# OpenTallas memory compiler (tools/mem_compiler), ASAP7 abstract view
VERSION 5.7 ;
BUSBITCHARS "[]" ;
DIVIDERCHAR "/" ;
PROPERTYDEFINITIONS
  MACRO width INTEGER ;
  MACRO depth INTEGER ;
  MACRO banks INTEGER ;
END PROPERTYDEFINITIONS
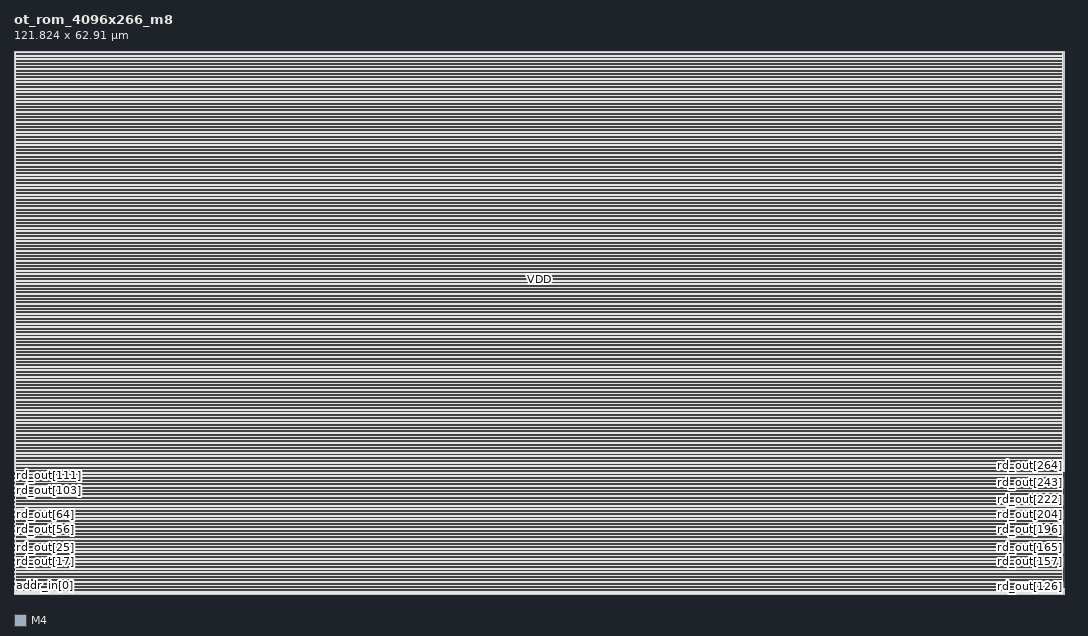
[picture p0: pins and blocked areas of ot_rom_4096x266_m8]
MACRO ot_rom_4096x266_m8
  PROPERTY width 266 ;
  PROPERTY depth 4096 ;
  PROPERTY banks 1 ;
  FOREIGN ot_rom_4096x266_m8 0 0 ;
  SYMMETRY X Y R90 ;
  SIZE 121.824 BY 62.910 ;
  CLASS BLOCK ;
  PIN clk
    DIRECTION INPUT ;
    USE CLOCK ;
    SHAPE ABUTMENT ;
    PORT
      LAYER M4 ;
      RECT 0.000 0.768 0.024 0.792 ;
    END
  END clk
  PIN ce_in
    DIRECTION INPUT ;
    USE SIGNAL ;
    SHAPE ABUTMENT ;
    PORT
      LAYER M4 ;
      RECT 0.000 0.864 0.024 0.888 ;
    END
  END ce_in
  PIN addr_in[0]
    DIRECTION INPUT ;
    USE SIGNAL ;
    SHAPE ABUTMENT ;
    PORT
      LAYER M4 ;
      RECT 0.000 0.960 0.024 0.984 ;
    END
  END addr_in[0]
  PIN addr_in[1]
    DIRECTION INPUT ;
    USE SIGNAL ;
    SHAPE ABUTMENT ;
    PORT
      LAYER M4 ;
      RECT 0.000 1.056 0.024 1.080 ;
    END
  END addr_in[1]
  PIN addr_in[2]
    DIRECTION INPUT ;
    USE SIGNAL ;
    SHAPE ABUTMENT ;
    PORT
      LAYER M4 ;
      RECT 0.000 1.152 0.024 1.176 ;
    END
  END addr_in[2]
  PIN addr_in[3]
    DIRECTION INPUT ;
    USE SIGNAL ;
    SHAPE ABUTMENT ;
    PORT
      LAYER M4 ;
      RECT 0.000 1.248 0.024 1.272 ;
    END
  END addr_in[3]
  PIN addr_in[4]
    DIRECTION INPUT ;
    USE SIGNAL ;
    SHAPE ABUTMENT ;
    PORT
      LAYER M4 ;
      RECT 0.000 1.344 0.024 1.368 ;
    END
  END addr_in[4]
  PIN addr_in[5]
    DIRECTION INPUT ;
    USE SIGNAL ;
    SHAPE ABUTMENT ;
    PORT
      LAYER M4 ;
      RECT 0.000 1.440 0.024 1.464 ;
    END
  END addr_in[5]
  PIN addr_in[6]
    DIRECTION INPUT ;
    USE SIGNAL ;
    SHAPE ABUTMENT ;
    PORT
      LAYER M4 ;
      RECT 0.000 1.536 0.024 1.560 ;
    END
  END addr_in[6]
  PIN addr_in[7]
    DIRECTION INPUT ;
    USE SIGNAL ;
    SHAPE ABUTMENT ;
    PORT
      LAYER M4 ;
      RECT 0.000 1.632 0.024 1.656 ;
    END
  END addr_in[7]
  PIN addr_in[8]
    DIRECTION INPUT ;
    USE SIGNAL ;
    SHAPE ABUTMENT ;
    PORT
      LAYER M4 ;
      RECT 0.000 1.728 0.024 1.752 ;
    END
  END addr_in[8]
  PIN addr_in[9]
    DIRECTION INPUT ;
    USE SIGNAL ;
    SHAPE ABUTMENT ;
    PORT
      LAYER M4 ;
      RECT 0.000 1.824 0.024 1.848 ;
    END
  END addr_in[9]
  PIN addr_in[10]
    DIRECTION INPUT ;
    USE SIGNAL ;
    SHAPE ABUTMENT ;
    PORT
      LAYER M4 ;
      RECT 0.000 1.920 0.024 1.944 ;
    END
  END addr_in[10]
  PIN addr_in[11]
    DIRECTION INPUT ;
    USE SIGNAL ;
    SHAPE ABUTMENT ;
    PORT
      LAYER M4 ;
      RECT 0.000 2.016 0.024 2.040 ;
    END
  END addr_in[11]
  PIN rd_out[0]
    DIRECTION OUTPUT ;
    USE SIGNAL ;
    SHAPE ABUTMENT ;
    PORT
      LAYER M4 ;
      RECT 0.000 2.112 0.024 2.136 ;
    END
  END rd_out[0]
  PIN rd_out[1]
    DIRECTION OUTPUT ;
    USE SIGNAL ;
    SHAPE ABUTMENT ;
    PORT
      LAYER M4 ;
      RECT 0.000 2.208 0.024 2.232 ;
    END
  END rd_out[1]
  PIN rd_out[2]
    DIRECTION OUTPUT ;
    USE SIGNAL ;
    SHAPE ABUTMENT ;
    PORT
      LAYER M4 ;
      RECT 0.000 2.304 0.024 2.328 ;
    END
  END rd_out[2]
  PIN rd_out[3]
    DIRECTION OUTPUT ;
    USE SIGNAL ;
    SHAPE ABUTMENT ;
    PORT
      LAYER M4 ;
      RECT 0.000 2.400 0.024 2.424 ;
    END
  END rd_out[3]
  PIN rd_out[4]
    DIRECTION OUTPUT ;
    USE SIGNAL ;
    SHAPE ABUTMENT ;
    PORT
      LAYER M4 ;
      RECT 0.000 2.496 0.024 2.520 ;
    END
  END rd_out[4]
  PIN rd_out[5]
    DIRECTION OUTPUT ;
    USE SIGNAL ;
    SHAPE ABUTMENT ;
    PORT
      LAYER M4 ;
      RECT 0.000 2.592 0.024 2.616 ;
    END
  END rd_out[5]
  PIN rd_out[6]
    DIRECTION OUTPUT ;
    USE SIGNAL ;
    SHAPE ABUTMENT ;
    PORT
      LAYER M4 ;
      RECT 0.000 2.688 0.024 2.712 ;
    END
  END rd_out[6]
  PIN rd_out[7]
    DIRECTION OUTPUT ;
    USE SIGNAL ;
    SHAPE ABUTMENT ;
    PORT
      LAYER M4 ;
      RECT 0.000 2.784 0.024 2.808 ;
    END
  END rd_out[7]
  PIN rd_out[8]
    DIRECTION OUTPUT ;
    USE SIGNAL ;
    SHAPE ABUTMENT ;
    PORT
      LAYER M4 ;
      RECT 0.000 2.880 0.024 2.904 ;
    END
  END rd_out[8]
  PIN rd_out[9]
    DIRECTION OUTPUT ;
    USE SIGNAL ;
    SHAPE ABUTMENT ;
    PORT
      LAYER M4 ;
      RECT 0.000 2.976 0.024 3.000 ;
    END
  END rd_out[9]
  PIN rd_out[10]
    DIRECTION OUTPUT ;
    USE SIGNAL ;
    SHAPE ABUTMENT ;
    PORT
      LAYER M4 ;
      RECT 0.000 3.072 0.024 3.096 ;
    END
  END rd_out[10]
  PIN rd_out[11]
    DIRECTION OUTPUT ;
    USE SIGNAL ;
    SHAPE ABUTMENT ;
    PORT
      LAYER M4 ;
      RECT 0.000 3.168 0.024 3.192 ;
    END
  END rd_out[11]
  PIN rd_out[12]
    DIRECTION OUTPUT ;
    USE SIGNAL ;
    SHAPE ABUTMENT ;
    PORT
      LAYER M4 ;
      RECT 0.000 3.264 0.024 3.288 ;
    END
  END rd_out[12]
  PIN rd_out[13]
    DIRECTION OUTPUT ;
    USE SIGNAL ;
    SHAPE ABUTMENT ;
    PORT
      LAYER M4 ;
      RECT 0.000 3.360 0.024 3.384 ;
    END
  END rd_out[13]
  PIN rd_out[14]
    DIRECTION OUTPUT ;
    USE SIGNAL ;
    SHAPE ABUTMENT ;
    PORT
      LAYER M4 ;
      RECT 0.000 3.456 0.024 3.480 ;
    END
  END rd_out[14]
  PIN rd_out[15]
    DIRECTION OUTPUT ;
    USE SIGNAL ;
    SHAPE ABUTMENT ;
    PORT
      LAYER M4 ;
      RECT 0.000 3.552 0.024 3.576 ;
    END
  END rd_out[15]
  PIN rd_out[16]
    DIRECTION OUTPUT ;
    USE SIGNAL ;
    SHAPE ABUTMENT ;
    PORT
      LAYER M4 ;
      RECT 0.000 3.648 0.024 3.672 ;
    END
  END rd_out[16]
  PIN rd_out[17]
    DIRECTION OUTPUT ;
    USE SIGNAL ;
    SHAPE ABUTMENT ;
    PORT
      LAYER M4 ;
      RECT 0.000 3.744 0.024 3.768 ;
    END
  END rd_out[17]
  PIN rd_out[18]
    DIRECTION OUTPUT ;
    USE SIGNAL ;
    SHAPE ABUTMENT ;
    PORT
      LAYER M4 ;
      RECT 0.000 3.840 0.024 3.864 ;
    END
  END rd_out[18]
  PIN rd_out[19]
    DIRECTION OUTPUT ;
    USE SIGNAL ;
    SHAPE ABUTMENT ;
    PORT
      LAYER M4 ;
      RECT 0.000 3.936 0.024 3.960 ;
    END
  END rd_out[19]
  PIN rd_out[20]
    DIRECTION OUTPUT ;
    USE SIGNAL ;
    SHAPE ABUTMENT ;
    PORT
      LAYER M4 ;
      RECT 0.000 4.032 0.024 4.056 ;
    END
  END rd_out[20]
  PIN rd_out[21]
    DIRECTION OUTPUT ;
    USE SIGNAL ;
    SHAPE ABUTMENT ;
    PORT
      LAYER M4 ;
      RECT 0.000 4.128 0.024 4.152 ;
    END
  END rd_out[21]
  PIN rd_out[22]
    DIRECTION OUTPUT ;
    USE SIGNAL ;
    SHAPE ABUTMENT ;
    PORT
      LAYER M4 ;
      RECT 0.000 4.224 0.024 4.248 ;
    END
  END rd_out[22]
  PIN rd_out[23]
    DIRECTION OUTPUT ;
    USE SIGNAL ;
    SHAPE ABUTMENT ;
    PORT
      LAYER M4 ;
      RECT 0.000 4.320 0.024 4.344 ;
    END
  END rd_out[23]
  PIN rd_out[24]
    DIRECTION OUTPUT ;
    USE SIGNAL ;
    SHAPE ABUTMENT ;
    PORT
      LAYER M4 ;
      RECT 0.000 4.416 0.024 4.440 ;
    END
  END rd_out[24]
  PIN rd_out[25]
    DIRECTION OUTPUT ;
    USE SIGNAL ;
    SHAPE ABUTMENT ;
    PORT
      LAYER M4 ;
      RECT 0.000 4.512 0.024 4.536 ;
    END
  END rd_out[25]
  PIN rd_out[26]
    DIRECTION OUTPUT ;
    USE SIGNAL ;
    SHAPE ABUTMENT ;
    PORT
      LAYER M4 ;
      RECT 0.000 4.608 0.024 4.632 ;
    END
  END rd_out[26]
  PIN rd_out[27]
    DIRECTION OUTPUT ;
    USE SIGNAL ;
    SHAPE ABUTMENT ;
    PORT
      LAYER M4 ;
      RECT 0.000 4.704 0.024 4.728 ;
    END
  END rd_out[27]
  PIN rd_out[28]
    DIRECTION OUTPUT ;
    USE SIGNAL ;
    SHAPE ABUTMENT ;
    PORT
      LAYER M4 ;
      RECT 0.000 4.800 0.024 4.824 ;
    END
  END rd_out[28]
  PIN rd_out[29]
    DIRECTION OUTPUT ;
    USE SIGNAL ;
    SHAPE ABUTMENT ;
    PORT
      LAYER M4 ;
      RECT 0.000 4.896 0.024 4.920 ;
    END
  END rd_out[29]
  PIN rd_out[30]
    DIRECTION OUTPUT ;
    USE SIGNAL ;
    SHAPE ABUTMENT ;
    PORT
      LAYER M4 ;
      RECT 0.000 4.992 0.024 5.016 ;
    END
  END rd_out[30]
  PIN rd_out[31]
    DIRECTION OUTPUT ;
    USE SIGNAL ;
    SHAPE ABUTMENT ;
    PORT
      LAYER M4 ;
      RECT 0.000 5.088 0.024 5.112 ;
    END
  END rd_out[31]
  PIN rd_out[32]
    DIRECTION OUTPUT ;
    USE SIGNAL ;
    SHAPE ABUTMENT ;
    PORT
      LAYER M4 ;
      RECT 0.000 5.184 0.024 5.208 ;
    END
  END rd_out[32]
  PIN rd_out[33]
    DIRECTION OUTPUT ;
    USE SIGNAL ;
    SHAPE ABUTMENT ;
    PORT
      LAYER M4 ;
      RECT 0.000 5.280 0.024 5.304 ;
    END
  END rd_out[33]
  PIN rd_out[34]
    DIRECTION OUTPUT ;
    USE SIGNAL ;
    SHAPE ABUTMENT ;
    PORT
      LAYER M4 ;
      RECT 0.000 5.376 0.024 5.400 ;
    END
  END rd_out[34]
  PIN rd_out[35]
    DIRECTION OUTPUT ;
    USE SIGNAL ;
    SHAPE ABUTMENT ;
    PORT
      LAYER M4 ;
      RECT 0.000 5.472 0.024 5.496 ;
    END
  END rd_out[35]
  PIN rd_out[36]
    DIRECTION OUTPUT ;
    USE SIGNAL ;
    SHAPE ABUTMENT ;
    PORT
      LAYER M4 ;
      RECT 0.000 5.568 0.024 5.592 ;
    END
  END rd_out[36]
  PIN rd_out[37]
    DIRECTION OUTPUT ;
    USE SIGNAL ;
    SHAPE ABUTMENT ;
    PORT
      LAYER M4 ;
      RECT 0.000 5.664 0.024 5.688 ;
    END
  END rd_out[37]
  PIN rd_out[38]
    DIRECTION OUTPUT ;
    USE SIGNAL ;
    SHAPE ABUTMENT ;
    PORT
      LAYER M4 ;
      RECT 0.000 5.760 0.024 5.784 ;
    END
  END rd_out[38]
  PIN rd_out[39]
    DIRECTION OUTPUT ;
    USE SIGNAL ;
    SHAPE ABUTMENT ;
    PORT
      LAYER M4 ;
      RECT 0.000 5.856 0.024 5.880 ;
    END
  END rd_out[39]
  PIN rd_out[40]
    DIRECTION OUTPUT ;
    USE SIGNAL ;
    SHAPE ABUTMENT ;
    PORT
      LAYER M4 ;
      RECT 0.000 5.952 0.024 5.976 ;
    END
  END rd_out[40]
  PIN rd_out[41]
    DIRECTION OUTPUT ;
    USE SIGNAL ;
    SHAPE ABUTMENT ;
    PORT
      LAYER M4 ;
      RECT 0.000 6.048 0.024 6.072 ;
    END
  END rd_out[41]
  PIN rd_out[42]
    DIRECTION OUTPUT ;
    USE SIGNAL ;
    SHAPE ABUTMENT ;
    PORT
      LAYER M4 ;
      RECT 0.000 6.144 0.024 6.168 ;
    END
  END rd_out[42]
  PIN rd_out[43]
    DIRECTION OUTPUT ;
    USE SIGNAL ;
    SHAPE ABUTMENT ;
    PORT
      LAYER M4 ;
      RECT 0.000 6.240 0.024 6.264 ;
    END
  END rd_out[43]
  PIN rd_out[44]
    DIRECTION OUTPUT ;
    USE SIGNAL ;
    SHAPE ABUTMENT ;
    PORT
      LAYER M4 ;
      RECT 0.000 6.336 0.024 6.360 ;
    END
  END rd_out[44]
  PIN rd_out[45]
    DIRECTION OUTPUT ;
    USE SIGNAL ;
    SHAPE ABUTMENT ;
    PORT
      LAYER M4 ;
      RECT 0.000 6.432 0.024 6.456 ;
    END
  END rd_out[45]
  PIN rd_out[46]
    DIRECTION OUTPUT ;
    USE SIGNAL ;
    SHAPE ABUTMENT ;
    PORT
      LAYER M4 ;
      RECT 0.000 6.528 0.024 6.552 ;
    END
  END rd_out[46]
  PIN rd_out[47]
    DIRECTION OUTPUT ;
    USE SIGNAL ;
    SHAPE ABUTMENT ;
    PORT
      LAYER M4 ;
      RECT 0.000 6.624 0.024 6.648 ;
    END
  END rd_out[47]
  PIN rd_out[48]
    DIRECTION OUTPUT ;
    USE SIGNAL ;
    SHAPE ABUTMENT ;
    PORT
      LAYER M4 ;
      RECT 0.000 6.720 0.024 6.744 ;
    END
  END rd_out[48]
  PIN rd_out[49]
    DIRECTION OUTPUT ;
    USE SIGNAL ;
    SHAPE ABUTMENT ;
    PORT
      LAYER M4 ;
      RECT 0.000 6.816 0.024 6.840 ;
    END
  END rd_out[49]
  PIN rd_out[50]
    DIRECTION OUTPUT ;
    USE SIGNAL ;
    SHAPE ABUTMENT ;
    PORT
      LAYER M4 ;
      RECT 0.000 6.912 0.024 6.936 ;
    END
  END rd_out[50]
  PIN rd_out[51]
    DIRECTION OUTPUT ;
    USE SIGNAL ;
    SHAPE ABUTMENT ;
    PORT
      LAYER M4 ;
      RECT 0.000 7.008 0.024 7.032 ;
    END
  END rd_out[51]
  PIN rd_out[52]
    DIRECTION OUTPUT ;
    USE SIGNAL ;
    SHAPE ABUTMENT ;
    PORT
      LAYER M4 ;
      RECT 0.000 7.104 0.024 7.128 ;
    END
  END rd_out[52]
  PIN rd_out[53]
    DIRECTION OUTPUT ;
    USE SIGNAL ;
    SHAPE ABUTMENT ;
    PORT
      LAYER M4 ;
      RECT 0.000 7.200 0.024 7.224 ;
    END
  END rd_out[53]
  PIN rd_out[54]
    DIRECTION OUTPUT ;
    USE SIGNAL ;
    SHAPE ABUTMENT ;
    PORT
      LAYER M4 ;
      RECT 0.000 7.296 0.024 7.320 ;
    END
  END rd_out[54]
  PIN rd_out[55]
    DIRECTION OUTPUT ;
    USE SIGNAL ;
    SHAPE ABUTMENT ;
    PORT
      LAYER M4 ;
      RECT 0.000 7.392 0.024 7.416 ;
    END
  END rd_out[55]
  PIN rd_out[56]
    DIRECTION OUTPUT ;
    USE SIGNAL ;
    SHAPE ABUTMENT ;
    PORT
      LAYER M4 ;
      RECT 0.000 7.488 0.024 7.512 ;
    END
  END rd_out[56]
  PIN rd_out[57]
    DIRECTION OUTPUT ;
    USE SIGNAL ;
    SHAPE ABUTMENT ;
    PORT
      LAYER M4 ;
      RECT 0.000 7.584 0.024 7.608 ;
    END
  END rd_out[57]
  PIN rd_out[58]
    DIRECTION OUTPUT ;
    USE SIGNAL ;
    SHAPE ABUTMENT ;
    PORT
      LAYER M4 ;
      RECT 0.000 7.680 0.024 7.704 ;
    END
  END rd_out[58]
  PIN rd_out[59]
    DIRECTION OUTPUT ;
    USE SIGNAL ;
    SHAPE ABUTMENT ;
    PORT
      LAYER M4 ;
      RECT 0.000 7.776 0.024 7.800 ;
    END
  END rd_out[59]
  PIN rd_out[60]
    DIRECTION OUTPUT ;
    USE SIGNAL ;
    SHAPE ABUTMENT ;
    PORT
      LAYER M4 ;
      RECT 0.000 7.872 0.024 7.896 ;
    END
  END rd_out[60]
  PIN rd_out[61]
    DIRECTION OUTPUT ;
    USE SIGNAL ;
    SHAPE ABUTMENT ;
    PORT
      LAYER M4 ;
      RECT 0.000 7.968 0.024 7.992 ;
    END
  END rd_out[61]
  PIN rd_out[62]
    DIRECTION OUTPUT ;
    USE SIGNAL ;
    SHAPE ABUTMENT ;
    PORT
      LAYER M4 ;
      RECT 0.000 8.064 0.024 8.088 ;
    END
  END rd_out[62]
  PIN rd_out[63]
    DIRECTION OUTPUT ;
    USE SIGNAL ;
    SHAPE ABUTMENT ;
    PORT
      LAYER M4 ;
      RECT 0.000 8.160 0.024 8.184 ;
    END
  END rd_out[63]
  PIN rd_out[64]
    DIRECTION OUTPUT ;
    USE SIGNAL ;
    SHAPE ABUTMENT ;
    PORT
      LAYER M4 ;
      RECT 0.000 8.256 0.024 8.280 ;
    END
  END rd_out[64]
  PIN rd_out[65]
    DIRECTION OUTPUT ;
    USE SIGNAL ;
    SHAPE ABUTMENT ;
    PORT
      LAYER M4 ;
      RECT 0.000 8.352 0.024 8.376 ;
    END
  END rd_out[65]
  PIN rd_out[66]
    DIRECTION OUTPUT ;
    USE SIGNAL ;
    SHAPE ABUTMENT ;
    PORT
      LAYER M4 ;
      RECT 0.000 8.448 0.024 8.472 ;
    END
  END rd_out[66]
  PIN rd_out[67]
    DIRECTION OUTPUT ;
    USE SIGNAL ;
    SHAPE ABUTMENT ;
    PORT
      LAYER M4 ;
      RECT 0.000 8.544 0.024 8.568 ;
    END
  END rd_out[67]
  PIN rd_out[68]
    DIRECTION OUTPUT ;
    USE SIGNAL ;
    SHAPE ABUTMENT ;
    PORT
      LAYER M4 ;
      RECT 0.000 8.640 0.024 8.664 ;
    END
  END rd_out[68]
  PIN rd_out[69]
    DIRECTION OUTPUT ;
    USE SIGNAL ;
    SHAPE ABUTMENT ;
    PORT
      LAYER M4 ;
      RECT 0.000 8.736 0.024 8.760 ;
    END
  END rd_out[69]
  PIN rd_out[70]
    DIRECTION OUTPUT ;
    USE SIGNAL ;
    SHAPE ABUTMENT ;
    PORT
      LAYER M4 ;
      RECT 0.000 8.832 0.024 8.856 ;
    END
  END rd_out[70]
  PIN rd_out[71]
    DIRECTION OUTPUT ;
    USE SIGNAL ;
    SHAPE ABUTMENT ;
    PORT
      LAYER M4 ;
      RECT 0.000 8.928 0.024 8.952 ;
    END
  END rd_out[71]
  PIN rd_out[72]
    DIRECTION OUTPUT ;
    USE SIGNAL ;
    SHAPE ABUTMENT ;
    PORT
      LAYER M4 ;
      RECT 0.000 9.024 0.024 9.048 ;
    END
  END rd_out[72]
  PIN rd_out[73]
    DIRECTION OUTPUT ;
    USE SIGNAL ;
    SHAPE ABUTMENT ;
    PORT
      LAYER M4 ;
      RECT 0.000 9.120 0.024 9.144 ;
    END
  END rd_out[73]
  PIN rd_out[74]
    DIRECTION OUTPUT ;
    USE SIGNAL ;
    SHAPE ABUTMENT ;
    PORT
      LAYER M4 ;
      RECT 0.000 9.216 0.024 9.240 ;
    END
  END rd_out[74]
  PIN rd_out[75]
    DIRECTION OUTPUT ;
    USE SIGNAL ;
    SHAPE ABUTMENT ;
    PORT
      LAYER M4 ;
      RECT 0.000 9.312 0.024 9.336 ;
    END
  END rd_out[75]
  PIN rd_out[76]
    DIRECTION OUTPUT ;
    USE SIGNAL ;
    SHAPE ABUTMENT ;
    PORT
      LAYER M4 ;
      RECT 0.000 9.408 0.024 9.432 ;
    END
  END rd_out[76]
  PIN rd_out[77]
    DIRECTION OUTPUT ;
    USE SIGNAL ;
    SHAPE ABUTMENT ;
    PORT
      LAYER M4 ;
      RECT 0.000 9.504 0.024 9.528 ;
    END
  END rd_out[77]
  PIN rd_out[78]
    DIRECTION OUTPUT ;
    USE SIGNAL ;
    SHAPE ABUTMENT ;
    PORT
      LAYER M4 ;
      RECT 0.000 9.600 0.024 9.624 ;
    END
  END rd_out[78]
  PIN rd_out[79]
    DIRECTION OUTPUT ;
    USE SIGNAL ;
    SHAPE ABUTMENT ;
    PORT
      LAYER M4 ;
      RECT 0.000 9.696 0.024 9.720 ;
    END
  END rd_out[79]
  PIN rd_out[80]
    DIRECTION OUTPUT ;
    USE SIGNAL ;
    SHAPE ABUTMENT ;
    PORT
      LAYER M4 ;
      RECT 0.000 9.792 0.024 9.816 ;
    END
  END rd_out[80]
  PIN rd_out[81]
    DIRECTION OUTPUT ;
    USE SIGNAL ;
    SHAPE ABUTMENT ;
    PORT
      LAYER M4 ;
      RECT 0.000 9.888 0.024 9.912 ;
    END
  END rd_out[81]
  PIN rd_out[82]
    DIRECTION OUTPUT ;
    USE SIGNAL ;
    SHAPE ABUTMENT ;
    PORT
      LAYER M4 ;
      RECT 0.000 9.984 0.024 10.008 ;
    END
  END rd_out[82]
  PIN rd_out[83]
    DIRECTION OUTPUT ;
    USE SIGNAL ;
    SHAPE ABUTMENT ;
    PORT
      LAYER M4 ;
      RECT 0.000 10.080 0.024 10.104 ;
    END
  END rd_out[83]
  PIN rd_out[84]
    DIRECTION OUTPUT ;
    USE SIGNAL ;
    SHAPE ABUTMENT ;
    PORT
      LAYER M4 ;
      RECT 0.000 10.176 0.024 10.200 ;
    END
  END rd_out[84]
  PIN rd_out[85]
    DIRECTION OUTPUT ;
    USE SIGNAL ;
    SHAPE ABUTMENT ;
    PORT
      LAYER M4 ;
      RECT 0.000 10.272 0.024 10.296 ;
    END
  END rd_out[85]
  PIN rd_out[86]
    DIRECTION OUTPUT ;
    USE SIGNAL ;
    SHAPE ABUTMENT ;
    PORT
      LAYER M4 ;
      RECT 0.000 10.368 0.024 10.392 ;
    END
  END rd_out[86]
  PIN rd_out[87]
    DIRECTION OUTPUT ;
    USE SIGNAL ;
    SHAPE ABUTMENT ;
    PORT
      LAYER M4 ;
      RECT 0.000 10.464 0.024 10.488 ;
    END
  END rd_out[87]
  PIN rd_out[88]
    DIRECTION OUTPUT ;
    USE SIGNAL ;
    SHAPE ABUTMENT ;
    PORT
      LAYER M4 ;
      RECT 0.000 10.560 0.024 10.584 ;
    END
  END rd_out[88]
  PIN rd_out[89]
    DIRECTION OUTPUT ;
    USE SIGNAL ;
    SHAPE ABUTMENT ;
    PORT
      LAYER M4 ;
      RECT 0.000 10.656 0.024 10.680 ;
    END
  END rd_out[89]
  PIN rd_out[90]
    DIRECTION OUTPUT ;
    USE SIGNAL ;
    SHAPE ABUTMENT ;
    PORT
      LAYER M4 ;
      RECT 0.000 10.752 0.024 10.776 ;
    END
  END rd_out[90]
  PIN rd_out[91]
    DIRECTION OUTPUT ;
    USE SIGNAL ;
    SHAPE ABUTMENT ;
    PORT
      LAYER M4 ;
      RECT 0.000 10.848 0.024 10.872 ;
    END
  END rd_out[91]
  PIN rd_out[92]
    DIRECTION OUTPUT ;
    USE SIGNAL ;
    SHAPE ABUTMENT ;
    PORT
      LAYER M4 ;
      RECT 0.000 10.944 0.024 10.968 ;
    END
  END rd_out[92]
  PIN rd_out[93]
    DIRECTION OUTPUT ;
    USE SIGNAL ;
    SHAPE ABUTMENT ;
    PORT
      LAYER M4 ;
      RECT 0.000 11.040 0.024 11.064 ;
    END
  END rd_out[93]
  PIN rd_out[94]
    DIRECTION OUTPUT ;
    USE SIGNAL ;
    SHAPE ABUTMENT ;
    PORT
      LAYER M4 ;
      RECT 0.000 11.136 0.024 11.160 ;
    END
  END rd_out[94]
  PIN rd_out[95]
    DIRECTION OUTPUT ;
    USE SIGNAL ;
    SHAPE ABUTMENT ;
    PORT
      LAYER M4 ;
      RECT 0.000 11.232 0.024 11.256 ;
    END
  END rd_out[95]
  PIN rd_out[96]
    DIRECTION OUTPUT ;
    USE SIGNAL ;
    SHAPE ABUTMENT ;
    PORT
      LAYER M4 ;
      RECT 0.000 11.328 0.024 11.352 ;
    END
  END rd_out[96]
  PIN rd_out[97]
    DIRECTION OUTPUT ;
    USE SIGNAL ;
    SHAPE ABUTMENT ;
    PORT
      LAYER M4 ;
      RECT 0.000 11.424 0.024 11.448 ;
    END
  END rd_out[97]
  PIN rd_out[98]
    DIRECTION OUTPUT ;
    USE SIGNAL ;
    SHAPE ABUTMENT ;
    PORT
      LAYER M4 ;
      RECT 0.000 11.520 0.024 11.544 ;
    END
  END rd_out[98]
  PIN rd_out[99]
    DIRECTION OUTPUT ;
    USE SIGNAL ;
    SHAPE ABUTMENT ;
    PORT
      LAYER M4 ;
      RECT 0.000 11.616 0.024 11.640 ;
    END
  END rd_out[99]
  PIN rd_out[100]
    DIRECTION OUTPUT ;
    USE SIGNAL ;
    SHAPE ABUTMENT ;
    PORT
      LAYER M4 ;
      RECT 0.000 11.712 0.024 11.736 ;
    END
  END rd_out[100]
  PIN rd_out[101]
    DIRECTION OUTPUT ;
    USE SIGNAL ;
    SHAPE ABUTMENT ;
    PORT
      LAYER M4 ;
      RECT 0.000 11.808 0.024 11.832 ;
    END
  END rd_out[101]
  PIN rd_out[102]
    DIRECTION OUTPUT ;
    USE SIGNAL ;
    SHAPE ABUTMENT ;
    PORT
      LAYER M4 ;
      RECT 0.000 11.904 0.024 11.928 ;
    END
  END rd_out[102]
  PIN rd_out[103]
    DIRECTION OUTPUT ;
    USE SIGNAL ;
    SHAPE ABUTMENT ;
    PORT
      LAYER M4 ;
      RECT 0.000 12.000 0.024 12.024 ;
    END
  END rd_out[103]
  PIN rd_out[104]
    DIRECTION OUTPUT ;
    USE SIGNAL ;
    SHAPE ABUTMENT ;
    PORT
      LAYER M4 ;
      RECT 0.000 12.096 0.024 12.120 ;
    END
  END rd_out[104]
  PIN rd_out[105]
    DIRECTION OUTPUT ;
    USE SIGNAL ;
    SHAPE ABUTMENT ;
    PORT
      LAYER M4 ;
      RECT 0.000 12.192 0.024 12.216 ;
    END
  END rd_out[105]
  PIN rd_out[106]
    DIRECTION OUTPUT ;
    USE SIGNAL ;
    SHAPE ABUTMENT ;
    PORT
      LAYER M4 ;
      RECT 0.000 12.288 0.024 12.312 ;
    END
  END rd_out[106]
  PIN rd_out[107]
    DIRECTION OUTPUT ;
    USE SIGNAL ;
    SHAPE ABUTMENT ;
    PORT
      LAYER M4 ;
      RECT 0.000 12.384 0.024 12.408 ;
    END
  END rd_out[107]
  PIN rd_out[108]
    DIRECTION OUTPUT ;
    USE SIGNAL ;
    SHAPE ABUTMENT ;
    PORT
      LAYER M4 ;
      RECT 0.000 12.480 0.024 12.504 ;
    END
  END rd_out[108]
  PIN rd_out[109]
    DIRECTION OUTPUT ;
    USE SIGNAL ;
    SHAPE ABUTMENT ;
    PORT
      LAYER M4 ;
      RECT 0.000 12.576 0.024 12.600 ;
    END
  END rd_out[109]
  PIN rd_out[110]
    DIRECTION OUTPUT ;
    USE SIGNAL ;
    SHAPE ABUTMENT ;
    PORT
      LAYER M4 ;
      RECT 0.000 12.672 0.024 12.696 ;
    END
  END rd_out[110]
  PIN rd_out[111]
    DIRECTION OUTPUT ;
    USE SIGNAL ;
    SHAPE ABUTMENT ;
    PORT
      LAYER M4 ;
      RECT 0.000 12.768 0.024 12.792 ;
    END
  END rd_out[111]
  PIN rd_out[112]
    DIRECTION OUTPUT ;
    USE SIGNAL ;
    SHAPE ABUTMENT ;
    PORT
      LAYER M4 ;
      RECT 0.000 12.864 0.024 12.888 ;
    END
  END rd_out[112]
  PIN rd_out[113]
    DIRECTION OUTPUT ;
    USE SIGNAL ;
    SHAPE ABUTMENT ;
    PORT
      LAYER M4 ;
      RECT 0.000 12.960 0.024 12.984 ;
    END
  END rd_out[113]
  PIN rd_out[114]
    DIRECTION OUTPUT ;
    USE SIGNAL ;
    SHAPE ABUTMENT ;
    PORT
      LAYER M4 ;
      RECT 0.000 13.056 0.024 13.080 ;
    END
  END rd_out[114]
  PIN rd_out[115]
    DIRECTION OUTPUT ;
    USE SIGNAL ;
    SHAPE ABUTMENT ;
    PORT
      LAYER M4 ;
      RECT 0.000 13.152 0.024 13.176 ;
    END
  END rd_out[115]
  PIN rd_out[116]
    DIRECTION OUTPUT ;
    USE SIGNAL ;
    SHAPE ABUTMENT ;
    PORT
      LAYER M4 ;
      RECT 0.000 13.248 0.024 13.272 ;
    END
  END rd_out[116]
  PIN rd_out[117]
    DIRECTION OUTPUT ;
    USE SIGNAL ;
    SHAPE ABUTMENT ;
    PORT
      LAYER M4 ;
      RECT 0.000 13.344 0.024 13.368 ;
    END
  END rd_out[117]
  PIN rd_out[118]
    DIRECTION OUTPUT ;
    USE SIGNAL ;
    SHAPE ABUTMENT ;
    PORT
      LAYER M4 ;
      RECT 0.000 13.440 0.024 13.464 ;
    END
  END rd_out[118]
  PIN rd_out[119]
    DIRECTION OUTPUT ;
    USE SIGNAL ;
    SHAPE ABUTMENT ;
    PORT
      LAYER M4 ;
      RECT 0.000 13.536 0.024 13.560 ;
    END
  END rd_out[119]
  PIN rd_out[120]
    DIRECTION OUTPUT ;
    USE SIGNAL ;
    SHAPE ABUTMENT ;
    PORT
      LAYER M4 ;
      RECT 0.000 13.632 0.024 13.656 ;
    END
  END rd_out[120]
  PIN rd_out[121]
    DIRECTION OUTPUT ;
    USE SIGNAL ;
    SHAPE ABUTMENT ;
    PORT
      LAYER M4 ;
      RECT 0.000 13.728 0.024 13.752 ;
    END
  END rd_out[121]
  PIN rd_out[122]
    DIRECTION OUTPUT ;
    USE SIGNAL ;
    SHAPE ABUTMENT ;
    PORT
      LAYER M4 ;
      RECT 0.000 13.824 0.024 13.848 ;
    END
  END rd_out[122]
  PIN rd_out[123]
    DIRECTION OUTPUT ;
    USE SIGNAL ;
    SHAPE ABUTMENT ;
    PORT
      LAYER M4 ;
      RECT 0.000 13.920 0.024 13.944 ;
    END
  END rd_out[123]
  PIN rd_out[124]
    DIRECTION OUTPUT ;
    USE SIGNAL ;
    SHAPE ABUTMENT ;
    PORT
      LAYER M4 ;
      RECT 0.000 14.016 0.024 14.040 ;
    END
  END rd_out[124]
  PIN rd_out[125]
    DIRECTION OUTPUT ;
    USE SIGNAL ;
    SHAPE ABUTMENT ;
    PORT
      LAYER M4 ;
      RECT 0.000 14.112 0.024 14.136 ;
    END
  END rd_out[125]
  PIN rd_out[126]
    DIRECTION OUTPUT ;
    USE SIGNAL ;
    SHAPE ABUTMENT ;
    PORT
      LAYER M4 ;
      RECT 121.800 0.768 121.824 0.792 ;
    END
  END rd_out[126]
  PIN rd_out[127]
    DIRECTION OUTPUT ;
    USE SIGNAL ;
    SHAPE ABUTMENT ;
    PORT
      LAYER M4 ;
      RECT 121.800 0.864 121.824 0.888 ;
    END
  END rd_out[127]
  PIN rd_out[128]
    DIRECTION OUTPUT ;
    USE SIGNAL ;
    SHAPE ABUTMENT ;
    PORT
      LAYER M4 ;
      RECT 121.800 0.960 121.824 0.984 ;
    END
  END rd_out[128]
  PIN rd_out[129]
    DIRECTION OUTPUT ;
    USE SIGNAL ;
    SHAPE ABUTMENT ;
    PORT
      LAYER M4 ;
      RECT 121.800 1.056 121.824 1.080 ;
    END
  END rd_out[129]
  PIN rd_out[130]
    DIRECTION OUTPUT ;
    USE SIGNAL ;
    SHAPE ABUTMENT ;
    PORT
      LAYER M4 ;
      RECT 121.800 1.152 121.824 1.176 ;
    END
  END rd_out[130]
  PIN rd_out[131]
    DIRECTION OUTPUT ;
    USE SIGNAL ;
    SHAPE ABUTMENT ;
    PORT
      LAYER M4 ;
      RECT 121.800 1.248 121.824 1.272 ;
    END
  END rd_out[131]
  PIN rd_out[132]
    DIRECTION OUTPUT ;
    USE SIGNAL ;
    SHAPE ABUTMENT ;
    PORT
      LAYER M4 ;
      RECT 121.800 1.344 121.824 1.368 ;
    END
  END rd_out[132]
  PIN rd_out[133]
    DIRECTION OUTPUT ;
    USE SIGNAL ;
    SHAPE ABUTMENT ;
    PORT
      LAYER M4 ;
      RECT 121.800 1.440 121.824 1.464 ;
    END
  END rd_out[133]
  PIN rd_out[134]
    DIRECTION OUTPUT ;
    USE SIGNAL ;
    SHAPE ABUTMENT ;
    PORT
      LAYER M4 ;
      RECT 121.800 1.536 121.824 1.560 ;
    END
  END rd_out[134]
  PIN rd_out[135]
    DIRECTION OUTPUT ;
    USE SIGNAL ;
    SHAPE ABUTMENT ;
    PORT
      LAYER M4 ;
      RECT 121.800 1.632 121.824 1.656 ;
    END
  END rd_out[135]
  PIN rd_out[136]
    DIRECTION OUTPUT ;
    USE SIGNAL ;
    SHAPE ABUTMENT ;
    PORT
      LAYER M4 ;
      RECT 121.800 1.728 121.824 1.752 ;
    END
  END rd_out[136]
  PIN rd_out[137]
    DIRECTION OUTPUT ;
    USE SIGNAL ;
    SHAPE ABUTMENT ;
    PORT
      LAYER M4 ;
      RECT 121.800 1.824 121.824 1.848 ;
    END
  END rd_out[137]
  PIN rd_out[138]
    DIRECTION OUTPUT ;
    USE SIGNAL ;
    SHAPE ABUTMENT ;
    PORT
      LAYER M4 ;
      RECT 121.800 1.920 121.824 1.944 ;
    END
  END rd_out[138]
  PIN rd_out[139]
    DIRECTION OUTPUT ;
    USE SIGNAL ;
    SHAPE ABUTMENT ;
    PORT
      LAYER M4 ;
      RECT 121.800 2.016 121.824 2.040 ;
    END
  END rd_out[139]
  PIN rd_out[140]
    DIRECTION OUTPUT ;
    USE SIGNAL ;
    SHAPE ABUTMENT ;
    PORT
      LAYER M4 ;
      RECT 121.800 2.112 121.824 2.136 ;
    END
  END rd_out[140]
  PIN rd_out[141]
    DIRECTION OUTPUT ;
    USE SIGNAL ;
    SHAPE ABUTMENT ;
    PORT
      LAYER M4 ;
      RECT 121.800 2.208 121.824 2.232 ;
    END
  END rd_out[141]
  PIN rd_out[142]
    DIRECTION OUTPUT ;
    USE SIGNAL ;
    SHAPE ABUTMENT ;
    PORT
      LAYER M4 ;
      RECT 121.800 2.304 121.824 2.328 ;
    END
  END rd_out[142]
  PIN rd_out[143]
    DIRECTION OUTPUT ;
    USE SIGNAL ;
    SHAPE ABUTMENT ;
    PORT
      LAYER M4 ;
      RECT 121.800 2.400 121.824 2.424 ;
    END
  END rd_out[143]
  PIN rd_out[144]
    DIRECTION OUTPUT ;
    USE SIGNAL ;
    SHAPE ABUTMENT ;
    PORT
      LAYER M4 ;
      RECT 121.800 2.496 121.824 2.520 ;
    END
  END rd_out[144]
  PIN rd_out[145]
    DIRECTION OUTPUT ;
    USE SIGNAL ;
    SHAPE ABUTMENT ;
    PORT
      LAYER M4 ;
      RECT 121.800 2.592 121.824 2.616 ;
    END
  END rd_out[145]
  PIN rd_out[146]
    DIRECTION OUTPUT ;
    USE SIGNAL ;
    SHAPE ABUTMENT ;
    PORT
      LAYER M4 ;
      RECT 121.800 2.688 121.824 2.712 ;
    END
  END rd_out[146]
  PIN rd_out[147]
    DIRECTION OUTPUT ;
    USE SIGNAL ;
    SHAPE ABUTMENT ;
    PORT
      LAYER M4 ;
      RECT 121.800 2.784 121.824 2.808 ;
    END
  END rd_out[147]
  PIN rd_out[148]
    DIRECTION OUTPUT ;
    USE SIGNAL ;
    SHAPE ABUTMENT ;
    PORT
      LAYER M4 ;
      RECT 121.800 2.880 121.824 2.904 ;
    END
  END rd_out[148]
  PIN rd_out[149]
    DIRECTION OUTPUT ;
    USE SIGNAL ;
    SHAPE ABUTMENT ;
    PORT
      LAYER M4 ;
      RECT 121.800 2.976 121.824 3.000 ;
    END
  END rd_out[149]
  PIN rd_out[150]
    DIRECTION OUTPUT ;
    USE SIGNAL ;
    SHAPE ABUTMENT ;
    PORT
      LAYER M4 ;
      RECT 121.800 3.072 121.824 3.096 ;
    END
  END rd_out[150]
  PIN rd_out[151]
    DIRECTION OUTPUT ;
    USE SIGNAL ;
    SHAPE ABUTMENT ;
    PORT
      LAYER M4 ;
      RECT 121.800 3.168 121.824 3.192 ;
    END
  END rd_out[151]
  PIN rd_out[152]
    DIRECTION OUTPUT ;
    USE SIGNAL ;
    SHAPE ABUTMENT ;
    PORT
      LAYER M4 ;
      RECT 121.800 3.264 121.824 3.288 ;
    END
  END rd_out[152]
  PIN rd_out[153]
    DIRECTION OUTPUT ;
    USE SIGNAL ;
    SHAPE ABUTMENT ;
    PORT
      LAYER M4 ;
      RECT 121.800 3.360 121.824 3.384 ;
    END
  END rd_out[153]
  PIN rd_out[154]
    DIRECTION OUTPUT ;
    USE SIGNAL ;
    SHAPE ABUTMENT ;
    PORT
      LAYER M4 ;
      RECT 121.800 3.456 121.824 3.480 ;
    END
  END rd_out[154]
  PIN rd_out[155]
    DIRECTION OUTPUT ;
    USE SIGNAL ;
    SHAPE ABUTMENT ;
    PORT
      LAYER M4 ;
      RECT 121.800 3.552 121.824 3.576 ;
    END
  END rd_out[155]
  PIN rd_out[156]
    DIRECTION OUTPUT ;
    USE SIGNAL ;
    SHAPE ABUTMENT ;
    PORT
      LAYER M4 ;
      RECT 121.800 3.648 121.824 3.672 ;
    END
  END rd_out[156]
  PIN rd_out[157]
    DIRECTION OUTPUT ;
    USE SIGNAL ;
    SHAPE ABUTMENT ;
    PORT
      LAYER M4 ;
      RECT 121.800 3.744 121.824 3.768 ;
    END
  END rd_out[157]
  PIN rd_out[158]
    DIRECTION OUTPUT ;
    USE SIGNAL ;
    SHAPE ABUTMENT ;
    PORT
      LAYER M4 ;
      RECT 121.800 3.840 121.824 3.864 ;
    END
  END rd_out[158]
  PIN rd_out[159]
    DIRECTION OUTPUT ;
    USE SIGNAL ;
    SHAPE ABUTMENT ;
    PORT
      LAYER M4 ;
      RECT 121.800 3.936 121.824 3.960 ;
    END
  END rd_out[159]
  PIN rd_out[160]
    DIRECTION OUTPUT ;
    USE SIGNAL ;
    SHAPE ABUTMENT ;
    PORT
      LAYER M4 ;
      RECT 121.800 4.032 121.824 4.056 ;
    END
  END rd_out[160]
  PIN rd_out[161]
    DIRECTION OUTPUT ;
    USE SIGNAL ;
    SHAPE ABUTMENT ;
    PORT
      LAYER M4 ;
      RECT 121.800 4.128 121.824 4.152 ;
    END
  END rd_out[161]
  PIN rd_out[162]
    DIRECTION OUTPUT ;
    USE SIGNAL ;
    SHAPE ABUTMENT ;
    PORT
      LAYER M4 ;
      RECT 121.800 4.224 121.824 4.248 ;
    END
  END rd_out[162]
  PIN rd_out[163]
    DIRECTION OUTPUT ;
    USE SIGNAL ;
    SHAPE ABUTMENT ;
    PORT
      LAYER M4 ;
      RECT 121.800 4.320 121.824 4.344 ;
    END
  END rd_out[163]
  PIN rd_out[164]
    DIRECTION OUTPUT ;
    USE SIGNAL ;
    SHAPE ABUTMENT ;
    PORT
      LAYER M4 ;
      RECT 121.800 4.416 121.824 4.440 ;
    END
  END rd_out[164]
  PIN rd_out[165]
    DIRECTION OUTPUT ;
    USE SIGNAL ;
    SHAPE ABUTMENT ;
    PORT
      LAYER M4 ;
      RECT 121.800 4.512 121.824 4.536 ;
    END
  END rd_out[165]
  PIN rd_out[166]
    DIRECTION OUTPUT ;
    USE SIGNAL ;
    SHAPE ABUTMENT ;
    PORT
      LAYER M4 ;
      RECT 121.800 4.608 121.824 4.632 ;
    END
  END rd_out[166]
  PIN rd_out[167]
    DIRECTION OUTPUT ;
    USE SIGNAL ;
    SHAPE ABUTMENT ;
    PORT
      LAYER M4 ;
      RECT 121.800 4.704 121.824 4.728 ;
    END
  END rd_out[167]
  PIN rd_out[168]
    DIRECTION OUTPUT ;
    USE SIGNAL ;
    SHAPE ABUTMENT ;
    PORT
      LAYER M4 ;
      RECT 121.800 4.800 121.824 4.824 ;
    END
  END rd_out[168]
  PIN rd_out[169]
    DIRECTION OUTPUT ;
    USE SIGNAL ;
    SHAPE ABUTMENT ;
    PORT
      LAYER M4 ;
      RECT 121.800 4.896 121.824 4.920 ;
    END
  END rd_out[169]
  PIN rd_out[170]
    DIRECTION OUTPUT ;
    USE SIGNAL ;
    SHAPE ABUTMENT ;
    PORT
      LAYER M4 ;
      RECT 121.800 4.992 121.824 5.016 ;
    END
  END rd_out[170]
  PIN rd_out[171]
    DIRECTION OUTPUT ;
    USE SIGNAL ;
    SHAPE ABUTMENT ;
    PORT
      LAYER M4 ;
      RECT 121.800 5.088 121.824 5.112 ;
    END
  END rd_out[171]
  PIN rd_out[172]
    DIRECTION OUTPUT ;
    USE SIGNAL ;
    SHAPE ABUTMENT ;
    PORT
      LAYER M4 ;
      RECT 121.800 5.184 121.824 5.208 ;
    END
  END rd_out[172]
  PIN rd_out[173]
    DIRECTION OUTPUT ;
    USE SIGNAL ;
    SHAPE ABUTMENT ;
    PORT
      LAYER M4 ;
      RECT 121.800 5.280 121.824 5.304 ;
    END
  END rd_out[173]
  PIN rd_out[174]
    DIRECTION OUTPUT ;
    USE SIGNAL ;
    SHAPE ABUTMENT ;
    PORT
      LAYER M4 ;
      RECT 121.800 5.376 121.824 5.400 ;
    END
  END rd_out[174]
  PIN rd_out[175]
    DIRECTION OUTPUT ;
    USE SIGNAL ;
    SHAPE ABUTMENT ;
    PORT
      LAYER M4 ;
      RECT 121.800 5.472 121.824 5.496 ;
    END
  END rd_out[175]
  PIN rd_out[176]
    DIRECTION OUTPUT ;
    USE SIGNAL ;
    SHAPE ABUTMENT ;
    PORT
      LAYER M4 ;
      RECT 121.800 5.568 121.824 5.592 ;
    END
  END rd_out[176]
  PIN rd_out[177]
    DIRECTION OUTPUT ;
    USE SIGNAL ;
    SHAPE ABUTMENT ;
    PORT
      LAYER M4 ;
      RECT 121.800 5.664 121.824 5.688 ;
    END
  END rd_out[177]
  PIN rd_out[178]
    DIRECTION OUTPUT ;
    USE SIGNAL ;
    SHAPE ABUTMENT ;
    PORT
      LAYER M4 ;
      RECT 121.800 5.760 121.824 5.784 ;
    END
  END rd_out[178]
  PIN rd_out[179]
    DIRECTION OUTPUT ;
    USE SIGNAL ;
    SHAPE ABUTMENT ;
    PORT
      LAYER M4 ;
      RECT 121.800 5.856 121.824 5.880 ;
    END
  END rd_out[179]
  PIN rd_out[180]
    DIRECTION OUTPUT ;
    USE SIGNAL ;
    SHAPE ABUTMENT ;
    PORT
      LAYER M4 ;
      RECT 121.800 5.952 121.824 5.976 ;
    END
  END rd_out[180]
  PIN rd_out[181]
    DIRECTION OUTPUT ;
    USE SIGNAL ;
    SHAPE ABUTMENT ;
    PORT
      LAYER M4 ;
      RECT 121.800 6.048 121.824 6.072 ;
    END
  END rd_out[181]
  PIN rd_out[182]
    DIRECTION OUTPUT ;
    USE SIGNAL ;
    SHAPE ABUTMENT ;
    PORT
      LAYER M4 ;
      RECT 121.800 6.144 121.824 6.168 ;
    END
  END rd_out[182]
  PIN rd_out[183]
    DIRECTION OUTPUT ;
    USE SIGNAL ;
    SHAPE ABUTMENT ;
    PORT
      LAYER M4 ;
      RECT 121.800 6.240 121.824 6.264 ;
    END
  END rd_out[183]
  PIN rd_out[184]
    DIRECTION OUTPUT ;
    USE SIGNAL ;
    SHAPE ABUTMENT ;
    PORT
      LAYER M4 ;
      RECT 121.800 6.336 121.824 6.360 ;
    END
  END rd_out[184]
  PIN rd_out[185]
    DIRECTION OUTPUT ;
    USE SIGNAL ;
    SHAPE ABUTMENT ;
    PORT
      LAYER M4 ;
      RECT 121.800 6.432 121.824 6.456 ;
    END
  END rd_out[185]
  PIN rd_out[186]
    DIRECTION OUTPUT ;
    USE SIGNAL ;
    SHAPE ABUTMENT ;
    PORT
      LAYER M4 ;
      RECT 121.800 6.528 121.824 6.552 ;
    END
  END rd_out[186]
  PIN rd_out[187]
    DIRECTION OUTPUT ;
    USE SIGNAL ;
    SHAPE ABUTMENT ;
    PORT
      LAYER M4 ;
      RECT 121.800 6.624 121.824 6.648 ;
    END
  END rd_out[187]
  PIN rd_out[188]
    DIRECTION OUTPUT ;
    USE SIGNAL ;
    SHAPE ABUTMENT ;
    PORT
      LAYER M4 ;
      RECT 121.800 6.720 121.824 6.744 ;
    END
  END rd_out[188]
  PIN rd_out[189]
    DIRECTION OUTPUT ;
    USE SIGNAL ;
    SHAPE ABUTMENT ;
    PORT
      LAYER M4 ;
      RECT 121.800 6.816 121.824 6.840 ;
    END
  END rd_out[189]
  PIN rd_out[190]
    DIRECTION OUTPUT ;
    USE SIGNAL ;
    SHAPE ABUTMENT ;
    PORT
      LAYER M4 ;
      RECT 121.800 6.912 121.824 6.936 ;
    END
  END rd_out[190]
  PIN rd_out[191]
    DIRECTION OUTPUT ;
    USE SIGNAL ;
    SHAPE ABUTMENT ;
    PORT
      LAYER M4 ;
      RECT 121.800 7.008 121.824 7.032 ;
    END
  END rd_out[191]
  PIN rd_out[192]
    DIRECTION OUTPUT ;
    USE SIGNAL ;
    SHAPE ABUTMENT ;
    PORT
      LAYER M4 ;
      RECT 121.800 7.104 121.824 7.128 ;
    END
  END rd_out[192]
  PIN rd_out[193]
    DIRECTION OUTPUT ;
    USE SIGNAL ;
    SHAPE ABUTMENT ;
    PORT
      LAYER M4 ;
      RECT 121.800 7.200 121.824 7.224 ;
    END
  END rd_out[193]
  PIN rd_out[194]
    DIRECTION OUTPUT ;
    USE SIGNAL ;
    SHAPE ABUTMENT ;
    PORT
      LAYER M4 ;
      RECT 121.800 7.296 121.824 7.320 ;
    END
  END rd_out[194]
  PIN rd_out[195]
    DIRECTION OUTPUT ;
    USE SIGNAL ;
    SHAPE ABUTMENT ;
    PORT
      LAYER M4 ;
      RECT 121.800 7.392 121.824 7.416 ;
    END
  END rd_out[195]
  PIN rd_out[196]
    DIRECTION OUTPUT ;
    USE SIGNAL ;
    SHAPE ABUTMENT ;
    PORT
      LAYER M4 ;
      RECT 121.800 7.488 121.824 7.512 ;
    END
  END rd_out[196]
  PIN rd_out[197]
    DIRECTION OUTPUT ;
    USE SIGNAL ;
    SHAPE ABUTMENT ;
    PORT
      LAYER M4 ;
      RECT 121.800 7.584 121.824 7.608 ;
    END
  END rd_out[197]
  PIN rd_out[198]
    DIRECTION OUTPUT ;
    USE SIGNAL ;
    SHAPE ABUTMENT ;
    PORT
      LAYER M4 ;
      RECT 121.800 7.680 121.824 7.704 ;
    END
  END rd_out[198]
  PIN rd_out[199]
    DIRECTION OUTPUT ;
    USE SIGNAL ;
    SHAPE ABUTMENT ;
    PORT
      LAYER M4 ;
      RECT 121.800 7.776 121.824 7.800 ;
    END
  END rd_out[199]
  PIN rd_out[200]
    DIRECTION OUTPUT ;
    USE SIGNAL ;
    SHAPE ABUTMENT ;
    PORT
      LAYER M4 ;
      RECT 121.800 7.872 121.824 7.896 ;
    END
  END rd_out[200]
  PIN rd_out[201]
    DIRECTION OUTPUT ;
    USE SIGNAL ;
    SHAPE ABUTMENT ;
    PORT
      LAYER M4 ;
      RECT 121.800 7.968 121.824 7.992 ;
    END
  END rd_out[201]
  PIN rd_out[202]
    DIRECTION OUTPUT ;
    USE SIGNAL ;
    SHAPE ABUTMENT ;
    PORT
      LAYER M4 ;
      RECT 121.800 8.064 121.824 8.088 ;
    END
  END rd_out[202]
  PIN rd_out[203]
    DIRECTION OUTPUT ;
    USE SIGNAL ;
    SHAPE ABUTMENT ;
    PORT
      LAYER M4 ;
      RECT 121.800 8.160 121.824 8.184 ;
    END
  END rd_out[203]
  PIN rd_out[204]
    DIRECTION OUTPUT ;
    USE SIGNAL ;
    SHAPE ABUTMENT ;
    PORT
      LAYER M4 ;
      RECT 121.800 8.256 121.824 8.280 ;
    END
  END rd_out[204]
  PIN rd_out[205]
    DIRECTION OUTPUT ;
    USE SIGNAL ;
    SHAPE ABUTMENT ;
    PORT
      LAYER M4 ;
      RECT 121.800 8.352 121.824 8.376 ;
    END
  END rd_out[205]
  PIN rd_out[206]
    DIRECTION OUTPUT ;
    USE SIGNAL ;
    SHAPE ABUTMENT ;
    PORT
      LAYER M4 ;
      RECT 121.800 8.448 121.824 8.472 ;
    END
  END rd_out[206]
  PIN rd_out[207]
    DIRECTION OUTPUT ;
    USE SIGNAL ;
    SHAPE ABUTMENT ;
    PORT
      LAYER M4 ;
      RECT 121.800 8.544 121.824 8.568 ;
    END
  END rd_out[207]
  PIN rd_out[208]
    DIRECTION OUTPUT ;
    USE SIGNAL ;
    SHAPE ABUTMENT ;
    PORT
      LAYER M4 ;
      RECT 121.800 8.640 121.824 8.664 ;
    END
  END rd_out[208]
  PIN rd_out[209]
    DIRECTION OUTPUT ;
    USE SIGNAL ;
    SHAPE ABUTMENT ;
    PORT
      LAYER M4 ;
      RECT 121.800 8.736 121.824 8.760 ;
    END
  END rd_out[209]
  PIN rd_out[210]
    DIRECTION OUTPUT ;
    USE SIGNAL ;
    SHAPE ABUTMENT ;
    PORT
      LAYER M4 ;
      RECT 121.800 8.832 121.824 8.856 ;
    END
  END rd_out[210]
  PIN rd_out[211]
    DIRECTION OUTPUT ;
    USE SIGNAL ;
    SHAPE ABUTMENT ;
    PORT
      LAYER M4 ;
      RECT 121.800 8.928 121.824 8.952 ;
    END
  END rd_out[211]
  PIN rd_out[212]
    DIRECTION OUTPUT ;
    USE SIGNAL ;
    SHAPE ABUTMENT ;
    PORT
      LAYER M4 ;
      RECT 121.800 9.024 121.824 9.048 ;
    END
  END rd_out[212]
  PIN rd_out[213]
    DIRECTION OUTPUT ;
    USE SIGNAL ;
    SHAPE ABUTMENT ;
    PORT
      LAYER M4 ;
      RECT 121.800 9.120 121.824 9.144 ;
    END
  END rd_out[213]
  PIN rd_out[214]
    DIRECTION OUTPUT ;
    USE SIGNAL ;
    SHAPE ABUTMENT ;
    PORT
      LAYER M4 ;
      RECT 121.800 9.216 121.824 9.240 ;
    END
  END rd_out[214]
  PIN rd_out[215]
    DIRECTION OUTPUT ;
    USE SIGNAL ;
    SHAPE ABUTMENT ;
    PORT
      LAYER M4 ;
      RECT 121.800 9.312 121.824 9.336 ;
    END
  END rd_out[215]
  PIN rd_out[216]
    DIRECTION OUTPUT ;
    USE SIGNAL ;
    SHAPE ABUTMENT ;
    PORT
      LAYER M4 ;
      RECT 121.800 9.408 121.824 9.432 ;
    END
  END rd_out[216]
  PIN rd_out[217]
    DIRECTION OUTPUT ;
    USE SIGNAL ;
    SHAPE ABUTMENT ;
    PORT
      LAYER M4 ;
      RECT 121.800 9.504 121.824 9.528 ;
    END
  END rd_out[217]
  PIN rd_out[218]
    DIRECTION OUTPUT ;
    USE SIGNAL ;
    SHAPE ABUTMENT ;
    PORT
      LAYER M4 ;
      RECT 121.800 9.600 121.824 9.624 ;
    END
  END rd_out[218]
  PIN rd_out[219]
    DIRECTION OUTPUT ;
    USE SIGNAL ;
    SHAPE ABUTMENT ;
    PORT
      LAYER M4 ;
      RECT 121.800 9.696 121.824 9.720 ;
    END
  END rd_out[219]
  PIN rd_out[220]
    DIRECTION OUTPUT ;
    USE SIGNAL ;
    SHAPE ABUTMENT ;
    PORT
      LAYER M4 ;
      RECT 121.800 9.792 121.824 9.816 ;
    END
  END rd_out[220]
  PIN rd_out[221]
    DIRECTION OUTPUT ;
    USE SIGNAL ;
    SHAPE ABUTMENT ;
    PORT
      LAYER M4 ;
      RECT 121.800 9.888 121.824 9.912 ;
    END
  END rd_out[221]
  PIN rd_out[222]
    DIRECTION OUTPUT ;
    USE SIGNAL ;
    SHAPE ABUTMENT ;
    PORT
      LAYER M4 ;
      RECT 121.800 9.984 121.824 10.008 ;
    END
  END rd_out[222]
  PIN rd_out[223]
    DIRECTION OUTPUT ;
    USE SIGNAL ;
    SHAPE ABUTMENT ;
    PORT
      LAYER M4 ;
      RECT 121.800 10.080 121.824 10.104 ;
    END
  END rd_out[223]
  PIN rd_out[224]
    DIRECTION OUTPUT ;
    USE SIGNAL ;
    SHAPE ABUTMENT ;
    PORT
      LAYER M4 ;
      RECT 121.800 10.176 121.824 10.200 ;
    END
  END rd_out[224]
  PIN rd_out[225]
    DIRECTION OUTPUT ;
    USE SIGNAL ;
    SHAPE ABUTMENT ;
    PORT
      LAYER M4 ;
      RECT 121.800 10.272 121.824 10.296 ;
    END
  END rd_out[225]
  PIN rd_out[226]
    DIRECTION OUTPUT ;
    USE SIGNAL ;
    SHAPE ABUTMENT ;
    PORT
      LAYER M4 ;
      RECT 121.800 10.368 121.824 10.392 ;
    END
  END rd_out[226]
  PIN rd_out[227]
    DIRECTION OUTPUT ;
    USE SIGNAL ;
    SHAPE ABUTMENT ;
    PORT
      LAYER M4 ;
      RECT 121.800 10.464 121.824 10.488 ;
    END
  END rd_out[227]
  PIN rd_out[228]
    DIRECTION OUTPUT ;
    USE SIGNAL ;
    SHAPE ABUTMENT ;
    PORT
      LAYER M4 ;
      RECT 121.800 10.560 121.824 10.584 ;
    END
  END rd_out[228]
  PIN rd_out[229]
    DIRECTION OUTPUT ;
    USE SIGNAL ;
    SHAPE ABUTMENT ;
    PORT
      LAYER M4 ;
      RECT 121.800 10.656 121.824 10.680 ;
    END
  END rd_out[229]
  PIN rd_out[230]
    DIRECTION OUTPUT ;
    USE SIGNAL ;
    SHAPE ABUTMENT ;
    PORT
      LAYER M4 ;
      RECT 121.800 10.752 121.824 10.776 ;
    END
  END rd_out[230]
  PIN rd_out[231]
    DIRECTION OUTPUT ;
    USE SIGNAL ;
    SHAPE ABUTMENT ;
    PORT
      LAYER M4 ;
      RECT 121.800 10.848 121.824 10.872 ;
    END
  END rd_out[231]
  PIN rd_out[232]
    DIRECTION OUTPUT ;
    USE SIGNAL ;
    SHAPE ABUTMENT ;
    PORT
      LAYER M4 ;
      RECT 121.800 10.944 121.824 10.968 ;
    END
  END rd_out[232]
  PIN rd_out[233]
    DIRECTION OUTPUT ;
    USE SIGNAL ;
    SHAPE ABUTMENT ;
    PORT
      LAYER M4 ;
      RECT 121.800 11.040 121.824 11.064 ;
    END
  END rd_out[233]
  PIN rd_out[234]
    DIRECTION OUTPUT ;
    USE SIGNAL ;
    SHAPE ABUTMENT ;
    PORT
      LAYER M4 ;
      RECT 121.800 11.136 121.824 11.160 ;
    END
  END rd_out[234]
  PIN rd_out[235]
    DIRECTION OUTPUT ;
    USE SIGNAL ;
    SHAPE ABUTMENT ;
    PORT
      LAYER M4 ;
      RECT 121.800 11.232 121.824 11.256 ;
    END
  END rd_out[235]
  PIN rd_out[236]
    DIRECTION OUTPUT ;
    USE SIGNAL ;
    SHAPE ABUTMENT ;
    PORT
      LAYER M4 ;
      RECT 121.800 11.328 121.824 11.352 ;
    END
  END rd_out[236]
  PIN rd_out[237]
    DIRECTION OUTPUT ;
    USE SIGNAL ;
    SHAPE ABUTMENT ;
    PORT
      LAYER M4 ;
      RECT 121.800 11.424 121.824 11.448 ;
    END
  END rd_out[237]
  PIN rd_out[238]
    DIRECTION OUTPUT ;
    USE SIGNAL ;
    SHAPE ABUTMENT ;
    PORT
      LAYER M4 ;
      RECT 121.800 11.520 121.824 11.544 ;
    END
  END rd_out[238]
  PIN rd_out[239]
    DIRECTION OUTPUT ;
    USE SIGNAL ;
    SHAPE ABUTMENT ;
    PORT
      LAYER M4 ;
      RECT 121.800 11.616 121.824 11.640 ;
    END
  END rd_out[239]
  PIN rd_out[240]
    DIRECTION OUTPUT ;
    USE SIGNAL ;
    SHAPE ABUTMENT ;
    PORT
      LAYER M4 ;
      RECT 121.800 11.712 121.824 11.736 ;
    END
  END rd_out[240]
  PIN rd_out[241]
    DIRECTION OUTPUT ;
    USE SIGNAL ;
    SHAPE ABUTMENT ;
    PORT
      LAYER M4 ;
      RECT 121.800 11.808 121.824 11.832 ;
    END
  END rd_out[241]
  PIN rd_out[242]
    DIRECTION OUTPUT ;
    USE SIGNAL ;
    SHAPE ABUTMENT ;
    PORT
      LAYER M4 ;
      RECT 121.800 11.904 121.824 11.928 ;
    END
  END rd_out[242]
  PIN rd_out[243]
    DIRECTION OUTPUT ;
    USE SIGNAL ;
    SHAPE ABUTMENT ;
    PORT
      LAYER M4 ;
      RECT 121.800 12.000 121.824 12.024 ;
    END
  END rd_out[243]
  PIN rd_out[244]
    DIRECTION OUTPUT ;
    USE SIGNAL ;
    SHAPE ABUTMENT ;
    PORT
      LAYER M4 ;
      RECT 121.800 12.096 121.824 12.120 ;
    END
  END rd_out[244]
  PIN rd_out[245]
    DIRECTION OUTPUT ;
    USE SIGNAL ;
    SHAPE ABUTMENT ;
    PORT
      LAYER M4 ;
      RECT 121.800 12.192 121.824 12.216 ;
    END
  END rd_out[245]
  PIN rd_out[246]
    DIRECTION OUTPUT ;
    USE SIGNAL ;
    SHAPE ABUTMENT ;
    PORT
      LAYER M4 ;
      RECT 121.800 12.288 121.824 12.312 ;
    END
  END rd_out[246]
  PIN rd_out[247]
    DIRECTION OUTPUT ;
    USE SIGNAL ;
    SHAPE ABUTMENT ;
    PORT
      LAYER M4 ;
      RECT 121.800 12.384 121.824 12.408 ;
    END
  END rd_out[247]
  PIN rd_out[248]
    DIRECTION OUTPUT ;
    USE SIGNAL ;
    SHAPE ABUTMENT ;
    PORT
      LAYER M4 ;
      RECT 121.800 12.480 121.824 12.504 ;
    END
  END rd_out[248]
  PIN rd_out[249]
    DIRECTION OUTPUT ;
    USE SIGNAL ;
    SHAPE ABUTMENT ;
    PORT
      LAYER M4 ;
      RECT 121.800 12.576 121.824 12.600 ;
    END
  END rd_out[249]
  PIN rd_out[250]
    DIRECTION OUTPUT ;
    USE SIGNAL ;
    SHAPE ABUTMENT ;
    PORT
      LAYER M4 ;
      RECT 121.800 12.672 121.824 12.696 ;
    END
  END rd_out[250]
  PIN rd_out[251]
    DIRECTION OUTPUT ;
    USE SIGNAL ;
    SHAPE ABUTMENT ;
    PORT
      LAYER M4 ;
      RECT 121.800 12.768 121.824 12.792 ;
    END
  END rd_out[251]
  PIN rd_out[252]
    DIRECTION OUTPUT ;
    USE SIGNAL ;
    SHAPE ABUTMENT ;
    PORT
      LAYER M4 ;
      RECT 121.800 12.864 121.824 12.888 ;
    END
  END rd_out[252]
  PIN rd_out[253]
    DIRECTION OUTPUT ;
    USE SIGNAL ;
    SHAPE ABUTMENT ;
    PORT
      LAYER M4 ;
      RECT 121.800 12.960 121.824 12.984 ;
    END
  END rd_out[253]
  PIN rd_out[254]
    DIRECTION OUTPUT ;
    USE SIGNAL ;
    SHAPE ABUTMENT ;
    PORT
      LAYER M4 ;
      RECT 121.800 13.056 121.824 13.080 ;
    END
  END rd_out[254]
  PIN rd_out[255]
    DIRECTION OUTPUT ;
    USE SIGNAL ;
    SHAPE ABUTMENT ;
    PORT
      LAYER M4 ;
      RECT 121.800 13.152 121.824 13.176 ;
    END
  END rd_out[255]
  PIN rd_out[256]
    DIRECTION OUTPUT ;
    USE SIGNAL ;
    SHAPE ABUTMENT ;
    PORT
      LAYER M4 ;
      RECT 121.800 13.248 121.824 13.272 ;
    END
  END rd_out[256]
  PIN rd_out[257]
    DIRECTION OUTPUT ;
    USE SIGNAL ;
    SHAPE ABUTMENT ;
    PORT
      LAYER M4 ;
      RECT 121.800 13.344 121.824 13.368 ;
    END
  END rd_out[257]
  PIN rd_out[258]
    DIRECTION OUTPUT ;
    USE SIGNAL ;
    SHAPE ABUTMENT ;
    PORT
      LAYER M4 ;
      RECT 121.800 13.440 121.824 13.464 ;
    END
  END rd_out[258]
  PIN rd_out[259]
    DIRECTION OUTPUT ;
    USE SIGNAL ;
    SHAPE ABUTMENT ;
    PORT
      LAYER M4 ;
      RECT 121.800 13.536 121.824 13.560 ;
    END
  END rd_out[259]
  PIN rd_out[260]
    DIRECTION OUTPUT ;
    USE SIGNAL ;
    SHAPE ABUTMENT ;
    PORT
      LAYER M4 ;
      RECT 121.800 13.632 121.824 13.656 ;
    END
  END rd_out[260]
  PIN rd_out[261]
    DIRECTION OUTPUT ;
    USE SIGNAL ;
    SHAPE ABUTMENT ;
    PORT
      LAYER M4 ;
      RECT 121.800 13.728 121.824 13.752 ;
    END
  END rd_out[261]
  PIN rd_out[262]
    DIRECTION OUTPUT ;
    USE SIGNAL ;
    SHAPE ABUTMENT ;
    PORT
      LAYER M4 ;
      RECT 121.800 13.824 121.824 13.848 ;
    END
  END rd_out[262]
  PIN rd_out[263]
    DIRECTION OUTPUT ;
    USE SIGNAL ;
    SHAPE ABUTMENT ;
    PORT
      LAYER M4 ;
      RECT 121.800 13.920 121.824 13.944 ;
    END
  END rd_out[263]
  PIN rd_out[264]
    DIRECTION OUTPUT ;
    USE SIGNAL ;
    SHAPE ABUTMENT ;
    PORT
      LAYER M4 ;
      RECT 121.800 14.016 121.824 14.040 ;
    END
  END rd_out[264]
  PIN rd_out[265]
    DIRECTION OUTPUT ;
    USE SIGNAL ;
    SHAPE ABUTMENT ;
    PORT
      LAYER M4 ;
      RECT 121.800 14.112 121.824 14.136 ;
    END
  END rd_out[265]
  PIN VDD
    DIRECTION INOUT ;
    USE POWER ;
    PORT
      LAYER M4 ;
      RECT 0.300 0.384 121.524 0.480 ;
      RECT 0.300 1.152 121.524 1.248 ;
      RECT 0.300 1.920 121.524 2.016 ;
      RECT 0.300 2.688 121.524 2.784 ;
      RECT 0.300 3.456 121.524 3.552 ;
      RECT 0.300 4.224 121.524 4.320 ;
      RECT 0.300 4.992 121.524 5.088 ;
      RECT 0.300 5.760 121.524 5.856 ;
      RECT 0.300 6.528 121.524 6.624 ;
      RECT 0.300 7.296 121.524 7.392 ;
      RECT 0.300 8.064 121.524 8.160 ;
      RECT 0.300 8.832 121.524 8.928 ;
      RECT 0.300 9.600 121.524 9.696 ;
      RECT 0.300 10.368 121.524 10.464 ;
      RECT 0.300 11.136 121.524 11.232 ;
      RECT 0.300 11.904 121.524 12.000 ;
      RECT 0.300 12.672 121.524 12.768 ;
      RECT 0.300 13.440 121.524 13.536 ;
      RECT 0.300 14.208 121.524 14.304 ;
      RECT 0.300 14.976 121.524 15.072 ;
      RECT 0.300 15.744 121.524 15.840 ;
      RECT 0.300 16.512 121.524 16.608 ;
      RECT 0.300 17.280 121.524 17.376 ;
      RECT 0.300 18.048 121.524 18.144 ;
      RECT 0.300 18.816 121.524 18.912 ;
      RECT 0.300 19.584 121.524 19.680 ;
      RECT 0.300 20.352 121.524 20.448 ;
      RECT 0.300 21.120 121.524 21.216 ;
      RECT 0.300 21.888 121.524 21.984 ;
      RECT 0.300 22.656 121.524 22.752 ;
      RECT 0.300 23.424 121.524 23.520 ;
      RECT 0.300 24.192 121.524 24.288 ;
      RECT 0.300 24.960 121.524 25.056 ;
      RECT 0.300 25.728 121.524 25.824 ;
      RECT 0.300 26.496 121.524 26.592 ;
      RECT 0.300 27.264 121.524 27.360 ;
      RECT 0.300 28.032 121.524 28.128 ;
      RECT 0.300 28.800 121.524 28.896 ;
      RECT 0.300 29.568 121.524 29.664 ;
      RECT 0.300 30.336 121.524 30.432 ;
      RECT 0.300 31.104 121.524 31.200 ;
      RECT 0.300 31.872 121.524 31.968 ;
      RECT 0.300 32.640 121.524 32.736 ;
      RECT 0.300 33.408 121.524 33.504 ;
      RECT 0.300 34.176 121.524 34.272 ;
      RECT 0.300 34.944 121.524 35.040 ;
      RECT 0.300 35.712 121.524 35.808 ;
      RECT 0.300 36.480 121.524 36.576 ;
      RECT 0.300 37.248 121.524 37.344 ;
      RECT 0.300 38.016 121.524 38.112 ;
      RECT 0.300 38.784 121.524 38.880 ;
      RECT 0.300 39.552 121.524 39.648 ;
      RECT 0.300 40.320 121.524 40.416 ;
      RECT 0.300 41.088 121.524 41.184 ;
      RECT 0.300 41.856 121.524 41.952 ;
      RECT 0.300 42.624 121.524 42.720 ;
      RECT 0.300 43.392 121.524 43.488 ;
      RECT 0.300 44.160 121.524 44.256 ;
      RECT 0.300 44.928 121.524 45.024 ;
      RECT 0.300 45.696 121.524 45.792 ;
      RECT 0.300 46.464 121.524 46.560 ;
      RECT 0.300 47.232 121.524 47.328 ;
      RECT 0.300 48.000 121.524 48.096 ;
      RECT 0.300 48.768 121.524 48.864 ;
      RECT 0.300 49.536 121.524 49.632 ;
      RECT 0.300 50.304 121.524 50.400 ;
      RECT 0.300 51.072 121.524 51.168 ;
      RECT 0.300 51.840 121.524 51.936 ;
      RECT 0.300 52.608 121.524 52.704 ;
      RECT 0.300 53.376 121.524 53.472 ;
      RECT 0.300 54.144 121.524 54.240 ;
      RECT 0.300 54.912 121.524 55.008 ;
      RECT 0.300 55.680 121.524 55.776 ;
      RECT 0.300 56.448 121.524 56.544 ;
      RECT 0.300 57.216 121.524 57.312 ;
      RECT 0.300 57.984 121.524 58.080 ;
      RECT 0.300 58.752 121.524 58.848 ;
      RECT 0.300 59.520 121.524 59.616 ;
      RECT 0.300 60.288 121.524 60.384 ;
      RECT 0.300 61.056 121.524 61.152 ;
      RECT 0.300 61.824 121.524 61.920 ;
      RECT 0.300 62.592 121.524 62.688 ;
    END
  END VDD
  PIN VSS
    DIRECTION INOUT ;
    USE GROUND ;
    PORT
      LAYER M4 ;
      RECT 0.300 0.768 121.524 0.864 ;
      RECT 0.300 1.536 121.524 1.632 ;
      RECT 0.300 2.304 121.524 2.400 ;
      RECT 0.300 3.072 121.524 3.168 ;
      RECT 0.300 3.840 121.524 3.936 ;
      RECT 0.300 4.608 121.524 4.704 ;
      RECT 0.300 5.376 121.524 5.472 ;
      RECT 0.300 6.144 121.524 6.240 ;
      RECT 0.300 6.912 121.524 7.008 ;
      RECT 0.300 7.680 121.524 7.776 ;
      RECT 0.300 8.448 121.524 8.544 ;
      RECT 0.300 9.216 121.524 9.312 ;
      RECT 0.300 9.984 121.524 10.080 ;
      RECT 0.300 10.752 121.524 10.848 ;
      RECT 0.300 11.520 121.524 11.616 ;
      RECT 0.300 12.288 121.524 12.384 ;
      RECT 0.300 13.056 121.524 13.152 ;
      RECT 0.300 13.824 121.524 13.920 ;
      RECT 0.300 14.592 121.524 14.688 ;
      RECT 0.300 15.360 121.524 15.456 ;
      RECT 0.300 16.128 121.524 16.224 ;
      RECT 0.300 16.896 121.524 16.992 ;
      RECT 0.300 17.664 121.524 17.760 ;
      RECT 0.300 18.432 121.524 18.528 ;
      RECT 0.300 19.200 121.524 19.296 ;
      RECT 0.300 19.968 121.524 20.064 ;
      RECT 0.300 20.736 121.524 20.832 ;
      RECT 0.300 21.504 121.524 21.600 ;
      RECT 0.300 22.272 121.524 22.368 ;
      RECT 0.300 23.040 121.524 23.136 ;
      RECT 0.300 23.808 121.524 23.904 ;
      RECT 0.300 24.576 121.524 24.672 ;
      RECT 0.300 25.344 121.524 25.440 ;
      RECT 0.300 26.112 121.524 26.208 ;
      RECT 0.300 26.880 121.524 26.976 ;
      RECT 0.300 27.648 121.524 27.744 ;
      RECT 0.300 28.416 121.524 28.512 ;
      RECT 0.300 29.184 121.524 29.280 ;
      RECT 0.300 29.952 121.524 30.048 ;
      RECT 0.300 30.720 121.524 30.816 ;
      RECT 0.300 31.488 121.524 31.584 ;
      RECT 0.300 32.256 121.524 32.352 ;
      RECT 0.300 33.024 121.524 33.120 ;
      RECT 0.300 33.792 121.524 33.888 ;
      RECT 0.300 34.560 121.524 34.656 ;
      RECT 0.300 35.328 121.524 35.424 ;
      RECT 0.300 36.096 121.524 36.192 ;
      RECT 0.300 36.864 121.524 36.960 ;
      RECT 0.300 37.632 121.524 37.728 ;
      RECT 0.300 38.400 121.524 38.496 ;
      RECT 0.300 39.168 121.524 39.264 ;
      RECT 0.300 39.936 121.524 40.032 ;
      RECT 0.300 40.704 121.524 40.800 ;
      RECT 0.300 41.472 121.524 41.568 ;
      RECT 0.300 42.240 121.524 42.336 ;
      RECT 0.300 43.008 121.524 43.104 ;
      RECT 0.300 43.776 121.524 43.872 ;
      RECT 0.300 44.544 121.524 44.640 ;
      RECT 0.300 45.312 121.524 45.408 ;
      RECT 0.300 46.080 121.524 46.176 ;
      RECT 0.300 46.848 121.524 46.944 ;
      RECT 0.300 47.616 121.524 47.712 ;
      RECT 0.300 48.384 121.524 48.480 ;
      RECT 0.300 49.152 121.524 49.248 ;
      RECT 0.300 49.920 121.524 50.016 ;
      RECT 0.300 50.688 121.524 50.784 ;
      RECT 0.300 51.456 121.524 51.552 ;
      RECT 0.300 52.224 121.524 52.320 ;
      RECT 0.300 52.992 121.524 53.088 ;
      RECT 0.300 53.760 121.524 53.856 ;
      RECT 0.300 54.528 121.524 54.624 ;
      RECT 0.300 55.296 121.524 55.392 ;
      RECT 0.300 56.064 121.524 56.160 ;
      RECT 0.300 56.832 121.524 56.928 ;
      RECT 0.300 57.600 121.524 57.696 ;
      RECT 0.300 58.368 121.524 58.464 ;
      RECT 0.300 59.136 121.524 59.232 ;
      RECT 0.300 59.904 121.524 60.000 ;
      RECT 0.300 60.672 121.524 60.768 ;
      RECT 0.300 61.440 121.524 61.536 ;
      RECT 0.300 62.208 121.524 62.304 ;
    END
  END VSS
  OBS
    LAYER M1 ;
    RECT 0 0 121.824 62.910 ;
    LAYER M2 ;
    RECT 0 0 121.824 62.910 ;
    LAYER M3 ;
    RECT 0 0 121.824 62.910 ;
    LAYER M4 ;
    RECT 0.072 0 121.752 62.910 ;
  END
END ot_rom_4096x266_m8

END LIBRARY
